VERSION 5.8 ;
BUSBITCHARS "[]" ;
DIVIDERCHAR "/" ;
UNITS
    DATABASE MICRONS 1000 ;
END UNITS

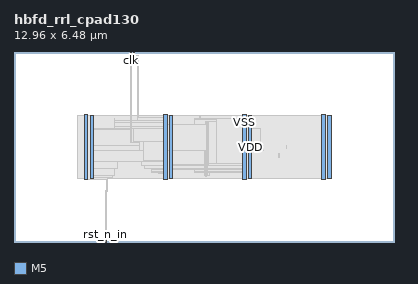
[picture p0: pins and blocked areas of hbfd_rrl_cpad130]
MACRO hbfd_rrl_cpad130
  FOREIGN hbfd_rrl_cpad130 0 0 ;
  CLASS BLOCK ;
  SIZE 12.96 BY 6.48 ;
  PIN clk
    DIRECTION INPUT ;
    USE SIGNAL ;
    PORT
      LAYER M5 ;
        RECT  3.984 6.396 4.008 6.48 ;
    END
  END clk
  PIN rst_n
    DIRECTION OUTPUT ;
    USE SIGNAL ;
    PORT
      LAYER M5 ;
        RECT  4.08 6.396 4.104 6.48 ;
    END
  END rst_n
  PIN rst_n_in
    DIRECTION INPUT ;
    USE SIGNAL ;
    PORT
      LAYER M5 ;
        RECT  3.12 0 3.144 0.084 ;
    END
  END rst_n_in
  PIN VDD
    DIRECTION INOUT ;
    USE POWER ;
    PORT
      LAYER M5 ;
        RECT  10.692 2.151 10.812 4.329 ;
        RECT  7.992 2.151 8.112 4.329 ;
        RECT  5.292 2.151 5.412 4.329 ;
        RECT  2.592 2.151 2.712 4.329 ;
    END
  END VDD
  PIN VSS
    DIRECTION INOUT ;
    USE GROUND ;
    PORT
      LAYER M5 ;
        RECT  10.5 2.137 10.62 4.343 ;
        RECT  7.8 2.137 7.92 4.343 ;
        RECT  5.1 2.137 5.22 4.343 ;
        RECT  2.4 2.137 2.52 4.343 ;
    END
  END VSS
  OBS
    LAYER RVTN ;
     RECT  2.16 2.16 10.8 2.295 ;
     RECT  2.16 2.565 10.8 2.835 ;
     RECT  2.16 3.105 10.8 3.375 ;
     RECT  2.16 3.645 10.8 3.915 ;
     RECT  2.16 4.185 10.8 4.32 ;
    LAYER RVTP ;
     RECT  2.16 2.295 10.8 2.565 ;
     RECT  2.16 2.835 10.8 3.105 ;
     RECT  2.16 3.375 10.8 3.645 ;
     RECT  2.16 3.915 10.8 4.185 ;
    LAYER M1 ;
     RECT  2.16 2.151 10.8 4.329 ;
    LAYER M2 ;
     RECT  2.16 2.151 10.8 4.329 ;
     RECT  10.8 2.421 10.812 4.059 ;
    LAYER M3 ;
     RECT  3.168 1.723 3.186 2.143 ;
     RECT  2.415 2.143 3.186 2.191 ;
     RECT  2.415 2.191 3.366 2.263 ;
     RECT  6.516 2.227 6.534 2.263 ;
     RECT  5.115 2.143 5.205 2.335 ;
     RECT  4.932 2.335 5.205 2.371 ;
     RECT  6.516 2.263 6.678 2.371 ;
     RECT  7.815 2.143 7.905 2.371 ;
     RECT  4.68 2.371 5.205 2.413 ;
     RECT  6.156 2.371 7.905 2.413 ;
     RECT  10.515 2.143 10.605 2.413 ;
     RECT  4.68 2.413 5.397 2.461 ;
     RECT  6.156 2.413 8.097 2.461 ;
     RECT  2.415 2.263 3.438 2.497 ;
     RECT  4.68 2.461 8.097 2.497 ;
     RECT  4.464 2.497 8.097 2.605 ;
     RECT  2.415 2.497 3.546 2.731 ;
     RECT  4.356 2.605 8.097 2.731 ;
     RECT  9.036 2.875 9.054 3.029 ;
     RECT  2.415 2.731 8.097 3.109 ;
     RECT  2.415 3.109 8.514 3.299 ;
     RECT  9.288 3.181 9.306 3.299 ;
     RECT  2.415 3.299 8.406 3.869 ;
     RECT  3.42 3.869 8.406 3.875 ;
     RECT  3.42 3.875 8.154 3.947 ;
     RECT  6.12 3.947 8.154 3.983 ;
     RECT  2.415 3.869 2.697 4.067 ;
     RECT  3.42 3.947 5.397 4.067 ;
     RECT  10.515 2.413 10.797 4.067 ;
     RECT  3.42 4.067 5.205 4.145 ;
     RECT  6.156 3.983 8.154 4.181 ;
     RECT  6.156 4.181 6.93 4.205 ;
     RECT  3.42 4.145 3.438 4.217 ;
     RECT  6.156 4.205 6.354 4.217 ;
     RECT  7.815 4.181 8.154 4.217 ;
     RECT  4.212 4.145 5.205 4.253 ;
     RECT  6.336 4.217 6.354 4.289 ;
     RECT  7.815 4.217 7.974 4.289 ;
     RECT  2.415 4.067 2.505 4.337 ;
     RECT  5.115 4.253 5.205 4.337 ;
     RECT  7.815 4.289 7.905 4.337 ;
     RECT  10.515 4.067 10.605 4.337 ;
     RECT  4.212 4.253 4.23 6.365 ;
    LAYER M4 ;
     RECT  2.408 2.148 2.512 4.332 ;
     RECT  2.512 2.148 2.704 4.062 ;
     RECT  3.109 1.728 3.197 1.752 ;
     RECT  2.704 3.84 3.973 3.864 ;
     RECT  3.973 3.408 4.061 3.864 ;
     RECT  4.069 6.336 4.241 6.36 ;
     RECT  4.061 3.408 4.273 3.432 ;
     RECT  4.273 3.12 4.417 3.432 ;
     RECT  4.417 2.784 5.108 3.432 ;
     RECT  5.108 2.148 5.212 4.332 ;
     RECT  5.212 2.418 5.404 4.062 ;
     RECT  5.404 2.64 6.505 4.008 ;
     RECT  6.505 2.256 6.517 4.008 ;
     RECT  6.517 2.256 6.589 4.104 ;
     RECT  6.589 2.64 6.617 4.104 ;
     RECT  6.617 2.688 6.901 4.104 ;
     RECT  6.901 2.688 7.808 4.2 ;
     RECT  7.808 2.148 7.912 4.332 ;
     RECT  7.912 2.418 8.093 4.2 ;
     RECT  8.093 2.418 8.104 4.062 ;
     RECT  10.508 2.148 10.612 4.332 ;
     RECT  10.612 2.418 10.804 4.062 ;
    LAYER M5 ;
     RECT  3.12 0.016 3.144 1.763 ;
     RECT  5.1 2.137 5.22 2.151 ;
     RECT  7.8 2.137 7.92 2.151 ;
     RECT  10.5 2.137 10.62 2.151 ;
     RECT  5.1 2.151 5.412 3.109 ;
     RECT  6.528 2.245 6.552 3.109 ;
     RECT  5.1 3.109 6.552 4.019 ;
     RECT  6.528 4.019 6.552 4.115 ;
     RECT  2.4 2.137 2.712 4.329 ;
     RECT  5.1 4.019 5.412 4.329 ;
     RECT  7.8 2.151 8.112 4.329 ;
     RECT  10.5 2.151 10.812 4.329 ;
     RECT  2.4 4.329 2.52 4.343 ;
     RECT  5.1 4.329 5.22 4.343 ;
     RECT  7.8 4.329 7.92 4.343 ;
     RECT  10.5 4.329 10.62 4.343 ;
     RECT  3.984 3.397 4.008 6.325 ;
     RECT  3.984 6.325 4.104 6.416 ;
  END
END hbfd_rrl_cpad130
END LIBRARY
